# Generated by innovus_enablement/scripts/gen_fakeram.py: abstract 64x7 SRAM.
# Geometry is an assumption (see script header), not PDK data.
VERSION 5.8 ;
BUSBITCHARS "[]" ;
DIVIDERCHAR "/" ;

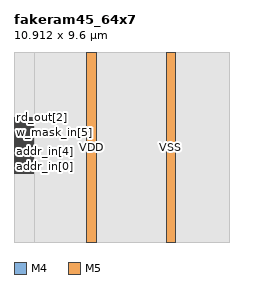
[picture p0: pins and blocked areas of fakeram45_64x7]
MACRO fakeram45_64x7
  CLASS BLOCK ;
  FOREIGN fakeram45_64x7 0 0 ;
  ORIGIN 0 0 ;
  SIZE 10.9120 BY 9.6000 ;
  SYMMETRY X Y R90 ;
  PIN clk
    DIRECTION INPUT ;
    USE CLOCK ;
    PORT
      LAYER M4 ;
        RECT 0 3.4800 0.9600 3.5280 ;
    END
  END clk
  PIN ce_in
    DIRECTION INPUT ;
    USE SIGNAL ;
    PORT
      LAYER M4 ;
        RECT 0 3.5760 0.9600 3.6240 ;
    END
  END ce_in
  PIN we_in
    DIRECTION INPUT ;
    USE SIGNAL ;
    PORT
      LAYER M4 ;
        RECT 0 3.6720 0.9600 3.7200 ;
    END
  END we_in
  PIN addr_in[0]
    DIRECTION INPUT ;
    USE SIGNAL ;
    PORT
      LAYER M4 ;
        RECT 0 3.7680 0.9600 3.8160 ;
    END
  END addr_in[0]
  PIN addr_in[1]
    DIRECTION INPUT ;
    USE SIGNAL ;
    PORT
      LAYER M4 ;
        RECT 0 3.8640 0.9600 3.9120 ;
    END
  END addr_in[1]
  PIN addr_in[2]
    DIRECTION INPUT ;
    USE SIGNAL ;
    PORT
      LAYER M4 ;
        RECT 0 3.9600 0.9600 4.0080 ;
    END
  END addr_in[2]
  PIN addr_in[3]
    DIRECTION INPUT ;
    USE SIGNAL ;
    PORT
      LAYER M4 ;
        RECT 0 4.0560 0.9600 4.1040 ;
    END
  END addr_in[3]
  PIN addr_in[4]
    DIRECTION INPUT ;
    USE SIGNAL ;
    PORT
      LAYER M4 ;
        RECT 0 4.1520 0.9600 4.2000 ;
    END
  END addr_in[4]
  PIN addr_in[5]
    DIRECTION INPUT ;
    USE SIGNAL ;
    PORT
      LAYER M4 ;
        RECT 0 4.2480 0.9600 4.2960 ;
    END
  END addr_in[5]
  PIN wd_in[0]
    DIRECTION INPUT ;
    USE SIGNAL ;
    PORT
      LAYER M4 ;
        RECT 0 4.3440 0.9600 4.3920 ;
    END
  END wd_in[0]
  PIN wd_in[1]
    DIRECTION INPUT ;
    USE SIGNAL ;
    PORT
      LAYER M4 ;
        RECT 0 4.4400 0.9600 4.4880 ;
    END
  END wd_in[1]
  PIN wd_in[2]
    DIRECTION INPUT ;
    USE SIGNAL ;
    PORT
      LAYER M4 ;
        RECT 0 4.5360 0.9600 4.5840 ;
    END
  END wd_in[2]
  PIN wd_in[3]
    DIRECTION INPUT ;
    USE SIGNAL ;
    PORT
      LAYER M4 ;
        RECT 0 4.6320 0.9600 4.6800 ;
    END
  END wd_in[3]
  PIN wd_in[4]
    DIRECTION INPUT ;
    USE SIGNAL ;
    PORT
      LAYER M4 ;
        RECT 0 4.7280 0.9600 4.7760 ;
    END
  END wd_in[4]
  PIN wd_in[5]
    DIRECTION INPUT ;
    USE SIGNAL ;
    PORT
      LAYER M4 ;
        RECT 0 4.8240 0.9600 4.8720 ;
    END
  END wd_in[5]
  PIN wd_in[6]
    DIRECTION INPUT ;
    USE SIGNAL ;
    PORT
      LAYER M4 ;
        RECT 0 4.9200 0.9600 4.9680 ;
    END
  END wd_in[6]
  PIN w_mask_in[0]
    DIRECTION INPUT ;
    USE SIGNAL ;
    PORT
      LAYER M4 ;
        RECT 0 5.0160 0.9600 5.0640 ;
    END
  END w_mask_in[0]
  PIN w_mask_in[1]
    DIRECTION INPUT ;
    USE SIGNAL ;
    PORT
      LAYER M4 ;
        RECT 0 5.1120 0.9600 5.1600 ;
    END
  END w_mask_in[1]
  PIN w_mask_in[2]
    DIRECTION INPUT ;
    USE SIGNAL ;
    PORT
      LAYER M4 ;
        RECT 0 5.2080 0.9600 5.2560 ;
    END
  END w_mask_in[2]
  PIN w_mask_in[3]
    DIRECTION INPUT ;
    USE SIGNAL ;
    PORT
      LAYER M4 ;
        RECT 0 5.3040 0.9600 5.3520 ;
    END
  END w_mask_in[3]
  PIN w_mask_in[4]
    DIRECTION INPUT ;
    USE SIGNAL ;
    PORT
      LAYER M4 ;
        RECT 0 5.4000 0.9600 5.4480 ;
    END
  END w_mask_in[4]
  PIN w_mask_in[5]
    DIRECTION INPUT ;
    USE SIGNAL ;
    PORT
      LAYER M4 ;
        RECT 0 5.4960 0.9600 5.5440 ;
    END
  END w_mask_in[5]
  PIN w_mask_in[6]
    DIRECTION INPUT ;
    USE SIGNAL ;
    PORT
      LAYER M4 ;
        RECT 0 5.5920 0.9600 5.6400 ;
    END
  END w_mask_in[6]
  PIN rd_out[0]
    DIRECTION OUTPUT ;
    USE SIGNAL ;
    PORT
      LAYER M4 ;
        RECT 0 5.6880 0.9600 5.7360 ;
    END
  END rd_out[0]
  PIN rd_out[1]
    DIRECTION OUTPUT ;
    USE SIGNAL ;
    PORT
      LAYER M4 ;
        RECT 0 5.7840 0.9600 5.8320 ;
    END
  END rd_out[1]
  PIN rd_out[2]
    DIRECTION OUTPUT ;
    USE SIGNAL ;
    PORT
      LAYER M4 ;
        RECT 0 5.8800 0.9600 5.9280 ;
    END
  END rd_out[2]
  PIN rd_out[3]
    DIRECTION OUTPUT ;
    USE SIGNAL ;
    PORT
      LAYER M4 ;
        RECT 0 5.9760 0.9600 6.0240 ;
    END
  END rd_out[3]
  PIN rd_out[4]
    DIRECTION OUTPUT ;
    USE SIGNAL ;
    PORT
      LAYER M4 ;
        RECT 0 6.0720 0.9600 6.1200 ;
    END
  END rd_out[4]
  PIN rd_out[5]
    DIRECTION OUTPUT ;
    USE SIGNAL ;
    PORT
      LAYER M4 ;
        RECT 0 6.1680 0.9600 6.2160 ;
    END
  END rd_out[5]
  PIN rd_out[6]
    DIRECTION OUTPUT ;
    USE SIGNAL ;
    PORT
      LAYER M4 ;
        RECT 0 6.2640 0.9600 6.3120 ;
    END
  END rd_out[6]
  PIN VDD
    DIRECTION INOUT ;
    USE POWER ;
    PORT
      LAYER M5 ;
        RECT 3.6800 0 4.1600 9.6000 ;
    END
  END VDD
  PIN VSS
    DIRECTION INOUT ;
    USE GROUND ;
    PORT
      LAYER M5 ;
        RECT 7.6800 0 8.1600 9.6000 ;
    END
  END VSS
  OBS
    LAYER M0 ;
      RECT 0 0 10.9120 9.6000 ;
    LAYER M1 ;
      RECT 0 0 10.9120 9.6000 ;
    LAYER M2 ;
      RECT 0 0 10.9120 9.6000 ;
    LAYER M3 ;
      RECT 0 0 10.9120 9.6000 ;
    LAYER VIA0 ;
      RECT 0 0 10.9120 9.6000 ;
    LAYER VIA1 ;
      RECT 0 0 10.9120 9.6000 ;
    LAYER VIA2 ;
      RECT 0 0 10.9120 9.6000 ;
    LAYER VIA3 ;
      RECT 0 0 10.9120 9.6000 ;
    LAYER M4 ;
      RECT 1.0560 0 10.9120 9.6000 ;
  END
END fakeram45_64x7

END LIBRARY
